# 
# ******************************************************************************
# *                                                                            *
# *                   Copyright (C) 2004-2010, Nangate Inc.                    *
# *                           All rights reserved.                             *
# *                                                                            *
# * Nangate and the Nangate logo are trademarks of Nangate Inc.                *
# *                                                                            *
# * All trademarks, logos, software marks, and trade names (collectively the   *
# * "Marks") in this program are proprietary to Nangate or other respective    *
# * owners that have granted Nangate the right and license to use such Marks.  *
# * You are not permitted to use the Marks without the prior written consent   *
# * of Nangate or such third party that may own the Marks.                     *
# *                                                                            *
# * This file has been provided pursuant to a License Agreement containing     *
# * restrictions on its use. This file contains valuable trade secrets and     *
# * proprietary information of Nangate Inc., and is protected by U.S. and      *
# * international laws and/or treaties.                                        *
# *                                                                            *
# * The copyright notice(s) in this file does not indicate actual or intended  *
# * publication of this file.                                                  *
# *                                                                            *
# *     NGLibraryCreator, v2010.08-HR32-SP3-2010-08-05 - build 1009061800      *
# *                                                                            *
# ******************************************************************************
# 
# 
# Running on brazil06.nangate.com.br for user Giancarlo Franciscatto (gfr).
# Local time is now Fri, 3 Dec 2010, 19:32:18.
# Main process id is 27821.

VERSION 5.6 ;
BUSBITCHARS "[]" ;
DIVIDERCHAR "/" ;

UNITS
  DATABASE MICRONS 2000 ;
END UNITS

MANUFACTURINGGRID 0.0050 ;

LAYER poly
  TYPE MASTERSLICE ;
END poly

LAYER active
  TYPE MASTERSLICE ;
END active

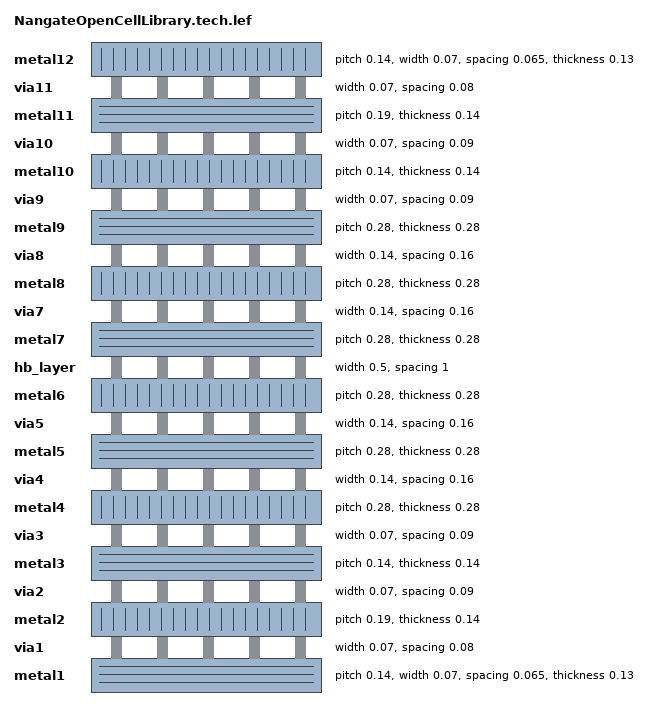
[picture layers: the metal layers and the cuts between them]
LAYER metal1
  TYPE ROUTING ;
  SPACING 0.065 ;
  WIDTH 0.07 ;
  PITCH 0.14 ;
  DIRECTION HORIZONTAL ;
  OFFSET 0.095 0.07 ;
  RESISTANCE RPERSQ 3.8 ;
  THICKNESS 0.13 ;
  HEIGHT 0.37 ;
  CAPACITANCE CPERSQDIST 7.7161e-05 ;
  EDGECAPACITANCE 2.7365e-05 ;
END metal1

LAYER via1
  TYPE CUT ;
  SPACING 0.08 ;
  WIDTH 0.07 ;
  RESISTANCE 5 ;
END via1

LAYER metal2
  TYPE ROUTING ;
  SPACINGTABLE 
    PARALLELRUNLENGTH    0.0000     0.3000     0.9000     1.8000     2.7000     4.0000     
      WIDTH 0.0000       0.0700     0.0700     0.0700     0.0700     0.0700     0.0700     
      WIDTH 0.0900       0.0700     0.0900     0.0900     0.0900     0.0900     0.0900     
      WIDTH 0.2700       0.0700     0.0900     0.2700     0.2700     0.2700     0.2700     
      WIDTH 0.5000       0.0700     0.0900     0.2700     0.5000     0.5000     0.5000     
      WIDTH 0.9000       0.0700     0.0900     0.2700     0.5000     0.9000     0.9000     
      WIDTH 1.5000       0.0700     0.0900     0.2700     0.5000     0.9000     1.5000      ;
  WIDTH 0.07 ;
  PITCH 0.19 ;
  DIRECTION VERTICAL ;
  OFFSET 0.095 0.07 ;
  RESISTANCE RPERSQ 2.5 ;
  THICKNESS 0.14 ;
  HEIGHT 0.62 ;
  CAPACITANCE CPERSQDIST 4.0896e-05 ;
  EDGECAPACITANCE 2.5157e-05 ;
END metal2

LAYER via2
  TYPE CUT ;
  SPACING 0.09 ;
  WIDTH 0.07 ;
  RESISTANCE 5 ;
END via2

LAYER metal3
  TYPE ROUTING ;
  SPACINGTABLE 
    PARALLELRUNLENGTH    0.0000     0.3000     0.9000     1.8000     2.7000     4.0000     
      WIDTH 0.0000       0.0700     0.0700     0.0700     0.0700     0.0700     0.0700     
      WIDTH 0.0900       0.0700     0.0900     0.0900     0.0900     0.0900     0.0900     
      WIDTH 0.2700       0.0700     0.0900     0.2700     0.2700     0.2700     0.2700     
      WIDTH 0.5000       0.0700     0.0900     0.2700     0.5000     0.5000     0.5000     
      WIDTH 0.9000       0.0700     0.0900     0.2700     0.5000     0.9000     0.9000     
      WIDTH 1.5000       0.0700     0.0900     0.2700     0.5000     0.9000     1.5000      ;
  WIDTH 0.07 ;
  PITCH 0.14 ;
  DIRECTION HORIZONTAL ;
  OFFSET 0.095 0.07 ;
  RESISTANCE RPERSQ 2.5 ;
  THICKNESS 0.14 ;
  HEIGHT 0.88 ;
  CAPACITANCE CPERSQDIST 2.7745e-05 ;
  EDGECAPACITANCE 2.5157e-05 ;
END metal3

LAYER via3
  TYPE CUT ;
  SPACING 0.09 ;
  WIDTH 0.07 ;
  RESISTANCE 5 ;
END via3

LAYER metal4
  TYPE ROUTING ;
  SPACINGTABLE 
    PARALLELRUNLENGTH    0.0000     0.9000     1.8000     2.7000     4.0000     
      WIDTH 0.0000       0.1400     0.1400     0.1400     0.1400     0.1400     
      WIDTH 0.2700       0.1400     0.2700     0.2700     0.2700     0.2700     
      WIDTH 0.5000       0.1400     0.2700     0.5000     0.5000     0.5000     
      WIDTH 0.9000       0.1400     0.2700     0.5000     0.9000     0.9000     
      WIDTH 1.5000       0.1400     0.2700     0.5000     0.9000     1.5000      ;
  WIDTH 0.14 ;
  PITCH 0.28 ;
  DIRECTION VERTICAL ;
  OFFSET 0.095 0.07 ;
  RESISTANCE RPERSQ 2.1 ;
  THICKNESS 0.28 ;
  HEIGHT 1.14 ;
  CAPACITANCE CPERSQDIST 2.0743e-05 ;
  EDGECAPACITANCE 3.0908e-05 ;
END metal4

LAYER via4
  TYPE CUT ;
  SPACING 0.16 ;
  WIDTH 0.14 ;
  RESISTANCE 3 ;
END via4

LAYER metal5
  TYPE ROUTING ;
  SPACINGTABLE 
    PARALLELRUNLENGTH    0.0000     0.9000     1.8000     2.7000     4.0000     
      WIDTH 0.0000       0.1400     0.1400     0.1400     0.1400     0.1400     
      WIDTH 0.2700       0.1400     0.2700     0.2700     0.2700     0.2700     
      WIDTH 0.5000       0.1400     0.2700     0.5000     0.5000     0.5000     
      WIDTH 0.9000       0.1400     0.2700     0.5000     0.9000     0.9000     
      WIDTH 1.5000       0.1400     0.2700     0.5000     0.9000     1.5000      ;
  WIDTH 0.14 ;
  PITCH 0.28 ;
  DIRECTION HORIZONTAL ;
  OFFSET 0.095 0.07 ;
  RESISTANCE RPERSQ 2.1 ;
  THICKNESS 0.28 ;
  HEIGHT 1.71 ;
  CAPACITANCE CPERSQDIST 1.3527e-05 ;
  EDGECAPACITANCE 2.3863e-06 ;
END metal5

LAYER via5
  TYPE CUT ;
  SPACING 0.16 ;
  WIDTH 0.14 ;
  RESISTANCE 3 ;
END via5

LAYER metal6
  TYPE ROUTING ;
  SPACINGTABLE 
    PARALLELRUNLENGTH    0.0000     0.9000     1.8000     2.7000     4.0000     
      WIDTH 0.0000       0.1400     0.1400     0.1400     0.1400     0.1400     
      WIDTH 0.2700       0.1400     0.2700     0.2700     0.2700     0.2700     
      WIDTH 0.5000       0.1400     0.2700     0.5000     0.5000     0.5000     
      WIDTH 0.9000       0.1400     0.2700     0.5000     0.9000     0.9000     
      WIDTH 1.5000       0.1400     0.2700     0.5000     0.9000     1.5000      ;
  WIDTH 0.14 ;
  PITCH 0.28 ;
  DIRECTION VERTICAL ;
  OFFSET 0.095 0.07 ;
  RESISTANCE RPERSQ 2.1 ;
  THICKNESS 0.28 ;
  HEIGHT 2.28 ;
  CAPACITANCE CPERSQDIST 1.0036e-05 ;
  EDGECAPACITANCE 2.3863e-05 ;
END metal6









LAYER hb_layer
  TYPE CUT ;
  SPACING 1 ;
  WIDTH 0.5 ;
  RESISTANCE 0.01 ;
END hb_layer









LAYER metal7
  TYPE ROUTING ;
  SPACINGTABLE 
    PARALLELRUNLENGTH    0.0000     0.9000     1.8000     2.7000     4.0000     
      WIDTH 0.0000       0.1400     0.1400     0.1400     0.1400     0.1400     
      WIDTH 0.2700       0.1400     0.2700     0.2700     0.2700     0.2700     
      WIDTH 0.5000       0.1400     0.2700     0.5000     0.5000     0.5000     
      WIDTH 0.9000       0.1400     0.2700     0.5000     0.9000     0.9000     
      WIDTH 1.5000       0.1400     0.2700     0.5000     0.9000     1.5000      ;
  WIDTH 0.14 ;
  PITCH 0.28 ;
  DIRECTION HORIZONTAL ;
  OFFSET 0.095 0.07 ;
  RESISTANCE RPERSQ 2.1 ;
  THICKNESS 0.28 ;
  HEIGHT 2.28 ;
  CAPACITANCE CPERSQDIST 1.0036e-05 ;
  EDGECAPACITANCE 2.3863e-05 ;
END metal7

LAYER via7
  TYPE CUT ;
  SPACING 0.16 ;
  WIDTH 0.14 ;
  RESISTANCE 3 ;
END via7

LAYER metal8
  TYPE ROUTING ;
  SPACINGTABLE 
    PARALLELRUNLENGTH    0.0000     0.9000     1.8000     2.7000     4.0000     
      WIDTH 0.0000       0.1400     0.1400     0.1400     0.1400     0.1400     
      WIDTH 0.2700       0.1400     0.2700     0.2700     0.2700     0.2700     
      WIDTH 0.5000       0.1400     0.2700     0.5000     0.5000     0.5000     
      WIDTH 0.9000       0.1400     0.2700     0.5000     0.9000     0.9000     
      WIDTH 1.5000       0.1400     0.2700     0.5000     0.9000     1.5000      ;
  WIDTH 0.14 ;
  PITCH 0.28 ;
  DIRECTION VERTICAL ;
  OFFSET 0.095 0.07 ;
  RESISTANCE RPERSQ 2.1 ;
  THICKNESS 0.28 ;
  HEIGHT 1.71 ;
  CAPACITANCE CPERSQDIST 1.3527e-05 ;
  EDGECAPACITANCE 2.3863e-06 ;
END metal8

LAYER via8
  TYPE CUT ;
  SPACING 0.16 ;
  WIDTH 0.14 ;
  RESISTANCE 3 ;
END via8

LAYER metal9
  TYPE ROUTING ;
  SPACINGTABLE 
    PARALLELRUNLENGTH    0.0000     0.9000     1.8000     2.7000     4.0000     
      WIDTH 0.0000       0.1400     0.1400     0.1400     0.1400     0.1400     
      WIDTH 0.2700       0.1400     0.2700     0.2700     0.2700     0.2700     
      WIDTH 0.5000       0.1400     0.2700     0.5000     0.5000     0.5000     
      WIDTH 0.9000       0.1400     0.2700     0.5000     0.9000     0.9000     
      WIDTH 1.5000       0.1400     0.2700     0.5000     0.9000     1.5000      ;
  WIDTH 0.14 ;
  PITCH 0.28 ;
  DIRECTION HORIZONTAL ;
  OFFSET 0.095 0.07 ;
  RESISTANCE RPERSQ 2.1 ;
  THICKNESS 0.28 ;
  HEIGHT 1.14 ;
  CAPACITANCE CPERSQDIST 2.0743e-05 ;
  EDGECAPACITANCE 3.0908e-05 ;
END metal9

LAYER via9
  TYPE CUT ;
  SPACING 0.09 ;
  WIDTH 0.07 ;
  RESISTANCE 5 ;
END via9

LAYER metal10
  TYPE ROUTING ;
  SPACINGTABLE 
    PARALLELRUNLENGTH    0.0000     0.3000     0.9000     1.8000     2.7000     4.0000     
      WIDTH 0.0000       0.0700     0.0700     0.0700     0.0700     0.0700     0.0700     
      WIDTH 0.0900       0.0700     0.0900     0.0900     0.0900     0.0900     0.0900     
      WIDTH 0.2700       0.0700     0.0900     0.2700     0.2700     0.2700     0.2700     
      WIDTH 0.5000       0.0700     0.0900     0.2700     0.5000     0.5000     0.5000     
      WIDTH 0.9000       0.0700     0.0900     0.2700     0.5000     0.9000     0.9000     
      WIDTH 1.5000       0.0700     0.0900     0.2700     0.5000     0.9000     1.5000      ;
  WIDTH 0.07 ;
  PITCH 0.14 ;
  DIRECTION VERTICAL ;
  OFFSET 0.095 0.07 ;
  RESISTANCE RPERSQ 2.5 ;
  THICKNESS 0.14 ;
  HEIGHT 0.88 ;
  CAPACITANCE CPERSQDIST 2.7745e-05 ;
  EDGECAPACITANCE 2.5157e-05 ;
END metal10

LAYER via10
  TYPE CUT ;
  SPACING 0.09 ;
  WIDTH 0.07 ;
  RESISTANCE 5 ;
END via10

LAYER metal11
  TYPE ROUTING ;
  SPACINGTABLE 
    PARALLELRUNLENGTH    0.0000     0.3000     0.9000     1.8000     2.7000     4.0000     
      WIDTH 0.0000       0.0700     0.0700     0.0700     0.0700     0.0700     0.0700     
      WIDTH 0.0900       0.0700     0.0900     0.0900     0.0900     0.0900     0.0900     
      WIDTH 0.2700       0.0700     0.0900     0.2700     0.2700     0.2700     0.2700     
      WIDTH 0.5000       0.0700     0.0900     0.2700     0.5000     0.5000     0.5000     
      WIDTH 0.9000       0.0700     0.0900     0.2700     0.5000     0.9000     0.9000     
      WIDTH 1.5000       0.0700     0.0900     0.2700     0.5000     0.9000     1.5000      ;
  WIDTH 0.07 ;
  PITCH 0.19 ;
  DIRECTION HORIZONTAL ;
  OFFSET 0.095 0.07 ;
  RESISTANCE RPERSQ 2.5 ;
  THICKNESS 0.14 ;
  HEIGHT 0.62 ;
  CAPACITANCE CPERSQDIST 4.0896e-05 ;
  EDGECAPACITANCE 2.5157e-05 ;
END metal11

LAYER via11
  TYPE CUT ;
  SPACING 0.08 ;
  WIDTH 0.07 ;
  RESISTANCE 5 ;
END via11

LAYER metal12
  TYPE ROUTING ;
  SPACING 0.065 ;
  WIDTH 0.07 ;
  PITCH 0.14 ;
  DIRECTION VERTICAL ;
  OFFSET 0.095 0.07 ;
  RESISTANCE RPERSQ 3.8 ;
  THICKNESS 0.13 ;
  HEIGHT 0.37 ;
  CAPACITANCE CPERSQDIST 7.7161e-05 ;
  EDGECAPACITANCE 2.7365e-05 ;
END metal12

LAYER OVERLAP
  TYPE OVERLAP ;
END OVERLAP

VIA via1_4 DEFAULT
  LAYER via1 ;
    RECT -0.035 -0.035 0.035 0.035 ;
  LAYER metal1 ;
    RECT -0.035 -0.07 0.035 0.07 ;
  LAYER metal2 ;
    RECT -0.035 -0.07 0.035 0.07 ;
END via1_4

VIA via1_0 DEFAULT
  LAYER via1 ;
    RECT -0.035 -0.035 0.035 0.035 ;
  LAYER metal1 ;
    RECT -0.07 -0.07 0.07 0.07 ;
  LAYER metal2 ;
    RECT -0.07 -0.07 0.07 0.07 ;
END via1_0

VIA via1_1 DEFAULT
  LAYER via1 ;
    RECT -0.035 -0.035 0.035 0.035 ;
  LAYER metal1 ;
    RECT -0.07 -0.07 0.07 0.07 ;
  LAYER metal2 ;
    RECT -0.035 -0.07 0.035 0.07 ;
END via1_1

VIA via1_2 DEFAULT
  LAYER via1 ;
    RECT -0.035 -0.035 0.035 0.035 ;
  LAYER metal1 ;
    RECT -0.07 -0.07 0.07 0.07 ;
  LAYER metal2 ;
    RECT -0.07 -0.035 0.07 0.035 ;
END via1_2

VIA via1_3 DEFAULT
  LAYER via1 ;
    RECT -0.035 -0.035 0.035 0.035 ;
  LAYER metal1 ;
    RECT -0.035 -0.07 0.035 0.07 ;
  LAYER metal2 ;
    RECT -0.07 -0.07 0.07 0.07 ;
END via1_3

VIA via1_5 DEFAULT
  LAYER via1 ;
    RECT -0.035 -0.035 0.035 0.035 ;
  LAYER metal1 ;
    RECT -0.035 -0.07 0.035 0.07 ;
  LAYER metal2 ;
    RECT -0.07 -0.035 0.07 0.035 ;
END via1_5

VIA via1_6 DEFAULT
  LAYER via1 ;
    RECT -0.035 -0.035 0.035 0.035 ;
  LAYER metal1 ;
    RECT -0.07 -0.035 0.07 0.035 ;
  LAYER metal2 ;
    RECT -0.07 -0.07 0.07 0.07 ;
END via1_6

VIA via1_7 DEFAULT
  LAYER via1 ;
    RECT -0.035 -0.035 0.035 0.035 ;
  LAYER metal1 ;
    RECT -0.07 -0.035 0.07 0.035 ;
  LAYER metal2 ;
    RECT -0.035 -0.07 0.035 0.07 ;
END via1_7

VIA via1_8 DEFAULT
  LAYER via1 ;
    RECT -0.035 -0.035 0.035 0.035 ;
  LAYER metal1 ;
    RECT -0.07 -0.035 0.07 0.035 ;
  LAYER metal2 ;
    RECT -0.07 -0.035 0.07 0.035 ;
END via1_8

VIA via2_8 DEFAULT
  LAYER via2 ;
    RECT -0.035 -0.035 0.035 0.035 ;
  LAYER metal2 ;
    RECT -0.07 -0.035 0.07 0.035 ;
  LAYER metal3 ;
    RECT -0.07 -0.035 0.07 0.035 ;
END via2_8

VIA via2_4 DEFAULT
  LAYER via2 ;
    RECT -0.035 -0.035 0.035 0.035 ;
  LAYER metal2 ;
    RECT -0.035 -0.07 0.035 0.07 ;
  LAYER metal3 ;
    RECT -0.035 -0.07 0.035 0.07 ;
END via2_4

VIA via2_5 DEFAULT
  LAYER via2 ;
    RECT -0.035 -0.035 0.035 0.035 ;
  LAYER metal2 ;
    RECT -0.035 -0.07 0.035 0.07 ;
  LAYER metal3 ;
    RECT -0.07 -0.035 0.07 0.035 ;
END via2_5

VIA via2_7 DEFAULT
  LAYER via2 ;
    RECT -0.035 -0.035 0.035 0.035 ;
  LAYER metal2 ;
    RECT -0.07 -0.035 0.07 0.035 ;
  LAYER metal3 ;
    RECT -0.035 -0.07 0.035 0.07 ;
END via2_7

VIA via2_6 DEFAULT
  LAYER via2 ;
    RECT -0.035 -0.035 0.035 0.035 ;
  LAYER metal2 ;
    RECT -0.07 -0.035 0.07 0.035 ;
  LAYER metal3 ;
    RECT -0.07 -0.07 0.07 0.07 ;
END via2_6

VIA via2_0 DEFAULT
  LAYER via2 ;
    RECT -0.035 -0.035 0.035 0.035 ;
  LAYER metal2 ;
    RECT -0.07 -0.07 0.07 0.07 ;
  LAYER metal3 ;
    RECT -0.07 -0.07 0.07 0.07 ;
END via2_0

VIA via2_1 DEFAULT
  LAYER via2 ;
    RECT -0.035 -0.035 0.035 0.035 ;
  LAYER metal2 ;
    RECT -0.07 -0.07 0.07 0.07 ;
  LAYER metal3 ;
    RECT -0.035 -0.07 0.035 0.07 ;
END via2_1

VIA via2_2 DEFAULT
  LAYER via2 ;
    RECT -0.035 -0.035 0.035 0.035 ;
  LAYER metal2 ;
    RECT -0.07 -0.07 0.07 0.07 ;
  LAYER metal3 ;
    RECT -0.07 -0.035 0.07 0.035 ;
END via2_2

VIA via2_3 DEFAULT
  LAYER via2 ;
    RECT -0.035 -0.035 0.035 0.035 ;
  LAYER metal2 ;
    RECT -0.035 -0.07 0.035 0.07 ;
  LAYER metal3 ;
    RECT -0.07 -0.07 0.07 0.07 ;
END via2_3

VIA via3_2 DEFAULT
  LAYER via3 ;
    RECT -0.035 -0.035 0.035 0.035 ;
  LAYER metal3 ;
    RECT -0.07 -0.035 0.07 0.035 ;
  LAYER metal4 ;
    RECT -0.07 -0.07 0.07 0.07 ;
END via3_2

VIA via3_0 DEFAULT
  LAYER via3 ;
    RECT -0.035 -0.035 0.035 0.035 ;
  LAYER metal3 ;
    RECT -0.07 -0.07 0.07 0.07 ;
  LAYER metal4 ;
    RECT -0.07 -0.07 0.07 0.07 ;
END via3_0

VIA via3_1 DEFAULT
  LAYER via3 ;
    RECT -0.035 -0.035 0.035 0.035 ;
  LAYER metal3 ;
    RECT -0.035 -0.07 0.035 0.07 ;
  LAYER metal4 ;
    RECT -0.07 -0.07 0.07 0.07 ;
END via3_1

VIA via4_0 DEFAULT
  LAYER via4 ;
    RECT -0.07 -0.07 0.07 0.07 ;
  LAYER metal4 ;
    RECT -0.07 -0.07 0.07 0.07 ;
  LAYER metal5 ;
    RECT -0.07 -0.07 0.07 0.07 ;
END via4_0

VIA via5_0 DEFAULT
  LAYER via5 ;
    RECT -0.07 -0.07 0.07 0.07 ;
  LAYER metal5 ;
    RECT -0.07 -0.07 0.07 0.07 ;
  LAYER metal6 ;
    RECT -0.07 -0.07 0.07 0.07 ;
END via5_0





VIA hb_layer_0 DEFAULT
  LAYER hb_layer ;
    RECT -0.25 -0.25 0.25 0.25 ;
  LAYER metal6 ;
    RECT -0.25 -0.25 0.25 0.25 ;
  LAYER metal7 ;
    RECT -0.25 -0.25 0.25 0.25 ;
END hb_layer_0





VIA via7_0 DEFAULT
  LAYER via7 ;
    RECT -0.07 -0.07 0.07 0.07 ;
  LAYER metal7 ;
    RECT -0.07 -0.07 0.07 0.07 ;
  LAYER metal8 ;
    RECT -0.07 -0.07 0.07 0.07 ;
END via7_0

VIA via8_0 DEFAULT
  LAYER via8 ;
    RECT -0.07 -0.07 0.07 0.07 ;
  LAYER metal8 ;
    RECT -0.07 -0.07 0.07 0.07 ;
  LAYER metal9 ;
    RECT -0.07 -0.07 0.07 0.07 ;
END via8_0

VIA via9_2 DEFAULT
  LAYER via9 ;
    RECT -0.035 -0.035 0.035 0.035 ;
  LAYER metal9 ;
    RECT -0.07 -0.035 0.07 0.035 ;
  LAYER metal10 ;
    RECT -0.07 -0.07 0.07 0.07 ;
END via9_2

VIA via9_0 DEFAULT
  LAYER via9 ;
    RECT -0.035 -0.035 0.035 0.035 ;
  LAYER metal9 ;
    RECT -0.07 -0.07 0.07 0.07 ;
  LAYER metal10 ;
    RECT -0.07 -0.07 0.07 0.07 ;
END via9_0

VIA via9_1 DEFAULT
  LAYER via9 ;
    RECT -0.035 -0.035 0.035 0.035 ;
  LAYER metal9 ;
    RECT -0.035 -0.07 0.035 0.07 ;
  LAYER metal10 ;
    RECT -0.07 -0.07 0.07 0.07 ;
END via9_1

VIA via10_8 DEFAULT
  LAYER via10 ;
    RECT -0.035 -0.035 0.035 0.035 ;
  LAYER metal10 ;
    RECT -0.07 -0.035 0.07 0.035 ;
  LAYER metal11 ;
    RECT -0.07 -0.035 0.07 0.035 ;
END via10_8

VIA via10_4 DEFAULT
  LAYER via10 ;
    RECT -0.035 -0.035 0.035 0.035 ;
  LAYER metal10 ;
    RECT -0.035 -0.07 0.035 0.07 ;
  LAYER metal11 ;
    RECT -0.035 -0.07 0.035 0.07 ;
END via10_4

VIA via10_5 DEFAULT
  LAYER via10 ;
    RECT -0.035 -0.035 0.035 0.035 ;
  LAYER metal10 ;
    RECT -0.035 -0.07 0.035 0.07 ;
  LAYER metal11 ;
    RECT -0.07 -0.035 0.07 0.035 ;
END via10_5

VIA via10_7 DEFAULT
  LAYER via10 ;
    RECT -0.035 -0.035 0.035 0.035 ;
  LAYER metal10 ;
    RECT -0.07 -0.035 0.07 0.035 ;
  LAYER metal11 ;
    RECT -0.035 -0.07 0.035 0.07 ;
END via10_7

VIA via10_6 DEFAULT
  LAYER via10 ;
    RECT -0.035 -0.035 0.035 0.035 ;
  LAYER metal10 ;
    RECT -0.07 -0.035 0.07 0.035 ;
  LAYER metal11 ;
    RECT -0.07 -0.07 0.07 0.07 ;
END via10_6

VIA via10_0 DEFAULT
  LAYER via10 ;
    RECT -0.035 -0.035 0.035 0.035 ;
  LAYER metal10 ;
    RECT -0.07 -0.07 0.07 0.07 ;
  LAYER metal11 ;
    RECT -0.07 -0.07 0.07 0.07 ;
END via10_0

VIA via10_1 DEFAULT
  LAYER via10 ;
    RECT -0.035 -0.035 0.035 0.035 ;
  LAYER metal10 ;
    RECT -0.07 -0.07 0.07 0.07 ;
  LAYER metal11 ;
    RECT -0.035 -0.07 0.035 0.07 ;
END via10_1

VIA via10_2 DEFAULT
  LAYER via10 ;
    RECT -0.035 -0.035 0.035 0.035 ;
  LAYER metal10 ;
    RECT -0.07 -0.07 0.07 0.07 ;
  LAYER metal11 ;
    RECT -0.07 -0.035 0.07 0.035 ;
END via10_2

VIA via10_3 DEFAULT
  LAYER via10 ;
    RECT -0.035 -0.035 0.035 0.035 ;
  LAYER metal10 ;
    RECT -0.035 -0.07 0.035 0.07 ;
  LAYER metal11 ;
    RECT -0.07 -0.07 0.07 0.07 ;
END via10_3

VIA via11_4 DEFAULT
  LAYER via11 ;
    RECT -0.035 -0.035 0.035 0.035 ;
  LAYER metal11 ;
    RECT -0.035 -0.07 0.035 0.07 ;
  LAYER metal12 ;
    RECT -0.035 -0.07 0.035 0.07 ;
END via11_4

VIA via11_0 DEFAULT
  LAYER via11 ;
    RECT -0.035 -0.035 0.035 0.035 ;
  LAYER metal11 ;
    RECT -0.07 -0.07 0.07 0.07 ;
  LAYER metal12 ;
    RECT -0.07 -0.07 0.07 0.07 ;
END via11_0

VIA via11_1 DEFAULT
  LAYER via11 ;
    RECT -0.035 -0.035 0.035 0.035 ;
  LAYER metal11 ;
    RECT -0.07 -0.07 0.07 0.07 ;
  LAYER metal12 ;
    RECT -0.035 -0.07 0.035 0.07 ;
END via11_1

VIA via11_2 DEFAULT
  LAYER via11 ;
    RECT -0.035 -0.035 0.035 0.035 ;
  LAYER metal11 ;
    RECT -0.07 -0.07 0.07 0.07 ;
  LAYER metal12 ;
    RECT -0.07 -0.035 0.07 0.035 ;
END via11_2

VIA via11_3 DEFAULT
  LAYER via11 ;
    RECT -0.035 -0.035 0.035 0.035 ;
  LAYER metal11 ;
    RECT -0.035 -0.07 0.035 0.07 ;
  LAYER metal12 ;
    RECT -0.07 -0.07 0.07 0.07 ;
END via11_3

VIA via11_5 DEFAULT
  LAYER via11 ;
    RECT -0.035 -0.035 0.035 0.035 ;
  LAYER metal11 ;
    RECT -0.035 -0.07 0.035 0.07 ;
  LAYER metal12 ;
    RECT -0.07 -0.035 0.07 0.035 ;
END via11_5

VIA via11_6 DEFAULT
  LAYER via11 ;
    RECT -0.035 -0.035 0.035 0.035 ;
  LAYER metal11 ;
    RECT -0.07 -0.035 0.07 0.035 ;
  LAYER metal12 ;
    RECT -0.07 -0.07 0.07 0.07 ;
END via11_6

VIA via11_7 DEFAULT
  LAYER via11 ;
    RECT -0.035 -0.035 0.035 0.035 ;
  LAYER metal11 ;
    RECT -0.07 -0.035 0.07 0.035 ;
  LAYER metal12 ;
    RECT -0.035 -0.07 0.035 0.07 ;
END via11_7

VIA via11_8 DEFAULT
  LAYER via11 ;
    RECT -0.035 -0.035 0.035 0.035 ;
  LAYER metal11 ;
    RECT -0.07 -0.035 0.07 0.035 ;
  LAYER metal12 ;
    RECT -0.07 -0.035 0.07 0.035 ;
END via11_8

VIARULE Via1Array-0 GENERATE
  LAYER metal1 ;
    ENCLOSURE 0.035 0.035 ;
  LAYER metal2 ;
    ENCLOSURE 0.035 0.035 ;
  LAYER via1 ;
    RECT -0.035 -0.035 0.035 0.035 ;
    SPACING 0.15 BY 0.15 ;
END Via1Array-0

VIARULE Via1Array-1 GENERATE
  LAYER metal1 ;
    ENCLOSURE 0 0.035 ;
  LAYER metal2 ;
    ENCLOSURE 0 0.035 ;
  LAYER via1 ;
    RECT -0.035 -0.035 0.035 0.035 ;
    SPACING 0.15 BY 0.15 ;
END Via1Array-1

VIARULE Via1Array-2 GENERATE
  LAYER metal1 ;
    ENCLOSURE 0.035 0 ;
  LAYER metal2 ;
    ENCLOSURE 0.035 0 ;
  LAYER via1 ;
    RECT -0.035 -0.035 0.035 0.035 ;
    SPACING 0.15 BY 0.15 ;
END Via1Array-2

VIARULE Via1Array-3 GENERATE
  LAYER metal1 ;
    ENCLOSURE 0 0.035 ;
  LAYER metal2 ;
    ENCLOSURE 0.035 0 ;
  LAYER via1 ;
    RECT -0.035 -0.035 0.035 0.035 ;
    SPACING 0.15 BY 0.15 ;
END Via1Array-3

VIARULE Via1Array-4 GENERATE
  LAYER metal1 ;
    ENCLOSURE 0.035 0 ;
  LAYER metal2 ;
    ENCLOSURE 0 0.035 ;
  LAYER via1 ;
    RECT -0.035 -0.035 0.035 0.035 ;
    SPACING 0.15 BY 0.15 ;
END Via1Array-4

VIARULE Via2Array-0 GENERATE
  LAYER metal2 ;
    ENCLOSURE 0.035 0.035 ;
  LAYER metal3 ;
    ENCLOSURE 0.035 0.035 ;
  LAYER via2 ;
    RECT -0.035 -0.035 0.035 0.035 ;
    SPACING 0.16 BY 0.16 ;
END Via2Array-0

VIARULE Via2Array-1 GENERATE
  LAYER metal2 ;
    ENCLOSURE 0 0.035 ;
  LAYER metal3 ;
    ENCLOSURE 0 0.035 ;
  LAYER via2 ;
    RECT -0.035 -0.035 0.035 0.035 ;
    SPACING 0.16 BY 0.16 ;
END Via2Array-1

VIARULE Via2Array-2 GENERATE
  LAYER metal2 ;
    ENCLOSURE 0.035 0 ;
  LAYER metal3 ;
    ENCLOSURE 0.035 0 ;
  LAYER via2 ;
    RECT -0.035 -0.035 0.035 0.035 ;
    SPACING 0.16 BY 0.16 ;
END Via2Array-2

VIARULE Via2Array-3 GENERATE
  LAYER metal2 ;
    ENCLOSURE 0 0.035 ;
  LAYER metal3 ;
    ENCLOSURE 0.035 0 ;
  LAYER via2 ;
    RECT -0.035 -0.035 0.035 0.035 ;
    SPACING 0.16 BY 0.16 ;
END Via2Array-3

VIARULE Via2Array-4 GENERATE
  LAYER metal2 ;
    ENCLOSURE 0.035 0 ;
  LAYER metal3 ;
    ENCLOSURE 0 0.035 ;
  LAYER via2 ;
    RECT -0.035 -0.035 0.035 0.035 ;
    SPACING 0.16 BY 0.16 ;
END Via2Array-4

VIARULE Via3Array-0 GENERATE
  LAYER metal3 ;
    ENCLOSURE 0.035 0.035 ;
  LAYER metal4 ;
    ENCLOSURE 0.035 0.035 ;
  LAYER via3 ;
    RECT -0.035 -0.035 0.035 0.035 ;
    SPACING 0.16 BY 0.16 ;
END Via3Array-0

VIARULE Via3Array-1 GENERATE
  LAYER metal3 ;
    ENCLOSURE 0 0.035 ;
  LAYER metal4 ;
    ENCLOSURE 0.035 0.035 ;
  LAYER via3 ;
    RECT -0.035 -0.035 0.035 0.035 ;
    SPACING 0.16 BY 0.16 ;
END Via3Array-1

VIARULE Via3Array-2 GENERATE
  LAYER metal3 ;
    ENCLOSURE 0.035 0 ;
  LAYER metal4 ;
    ENCLOSURE 0.035 0.035 ;
  LAYER via3 ;
    RECT -0.035 -0.035 0.035 0.035 ;
    SPACING 0.16 BY 0.16 ;
END Via3Array-2

VIARULE Via4Array-0 GENERATE
  LAYER metal4 ;
    ENCLOSURE 0 0 ;
  LAYER metal5 ;
    ENCLOSURE 0 0 ;
  LAYER via4 ;
    RECT -0.07 -0.07 0.07 0.07 ;
    SPACING 0.3 BY 0.3 ;
END Via4Array-0

VIARULE Via5Array-0 GENERATE
  LAYER metal5 ;
    ENCLOSURE 0 0 ;
  LAYER metal6 ;
    ENCLOSURE 0 0 ;
  LAYER via5 ;
    RECT -0.07 -0.07 0.07 0.07 ;
    SPACING 0.3 BY 0.3 ;
END Via5Array-0





VIARULE hb_layerArray-0 GENERATE
  LAYER metal7 ;
    ENCLOSURE 0 0 ;
  LAYER metal6 ;
    ENCLOSURE 0 0 ;
  LAYER hb_layer ;
    RECT -0.25 -0.25 0.25 0.25 ;
    SPACING 1 BY 1 ;
END hb_layerArray-0





VIARULE Via7Array-0 GENERATE
  LAYER metal7 ;
    ENCLOSURE 0 0 ;
  LAYER metal8 ;
    ENCLOSURE 0 0 ;
  LAYER via7 ;
    RECT -0.07 -0.07 0.07 0.07 ;
    SPACING 0.3 BY 0.3 ;
END Via7Array-0

VIARULE Via8Array-0 GENERATE
  LAYER metal8 ;
    ENCLOSURE 0 0 ;
  LAYER metal9 ;
    ENCLOSURE 0 0 ;
  LAYER via8 ;
    RECT -0.07 -0.07 0.07 0.07 ;
    SPACING 0.3 BY 0.3 ;
END Via8Array-0

VIARULE Via9Array-0 GENERATE
  LAYER metal9 ;
    ENCLOSURE 0.035 0.035 ;
  LAYER metal10 ;
    ENCLOSURE 0.035 0.035 ;
  LAYER via9 ;
    RECT -0.035 -0.035 0.035 0.035 ;
    SPACING 0.16 BY 0.16 ;
END Via9Array-0

VIARULE Via9Array-1 GENERATE
  LAYER metal9 ;
    ENCLOSURE 0 0.035 ;
  LAYER metal10 ;
    ENCLOSURE 0.035 0.035 ;
  LAYER via9 ;
    RECT -0.035 -0.035 0.035 0.035 ;
    SPACING 0.16 BY 0.16 ;
END Via9Array-1

VIARULE Via9Array-2 GENERATE
  LAYER metal9 ;
    ENCLOSURE 0.035 0 ;
  LAYER metal10 ;
    ENCLOSURE 0.035 0.035 ;
  LAYER via9 ;
    RECT -0.035 -0.035 0.035 0.035 ;
    SPACING 0.16 BY 0.16 ;
END Via9Array-2

VIARULE Via10Array-0 GENERATE
  LAYER metal10 ;
    ENCLOSURE 0.035 0.035 ;
  LAYER metal11 ;
    ENCLOSURE 0.035 0.035 ;
  LAYER via10 ;
    RECT -0.035 -0.035 0.035 0.035 ;
    SPACING 0.16 BY 0.16 ;
END Via10Array-0

VIARULE Via10Array-1 GENERATE
  LAYER metal10 ;
    ENCLOSURE 0 0.035 ;
  LAYER metal11 ;
    ENCLOSURE 0 0.035 ;
  LAYER via10 ;
    RECT -0.035 -0.035 0.035 0.035 ;
    SPACING 0.16 BY 0.16 ;
END Via10Array-1

VIARULE Via10Array-2 GENERATE
  LAYER metal10 ;
    ENCLOSURE 0.035 0 ;
  LAYER metal11 ;
    ENCLOSURE 0.035 0 ;
  LAYER via10 ;
    RECT -0.035 -0.035 0.035 0.035 ;
    SPACING 0.16 BY 0.16 ;
END Via10Array-2

VIARULE Via10Array-3 GENERATE
  LAYER metal10 ;
    ENCLOSURE 0 0.035 ;
  LAYER metal11 ;
    ENCLOSURE 0.035 0 ;
  LAYER via10 ;
    RECT -0.035 -0.035 0.035 0.035 ;
    SPACING 0.16 BY 0.16 ;
END Via10Array-3

VIARULE Via10Array-4 GENERATE
  LAYER metal10 ;
    ENCLOSURE 0.035 0 ;
  LAYER metal11 ;
    ENCLOSURE 0 0.035 ;
  LAYER via10 ;
    RECT -0.035 -0.035 0.035 0.035 ;
    SPACING 0.16 BY 0.16 ;
END Via10Array-4

VIARULE Via11Array-0 GENERATE
  LAYER metal11 ;
    ENCLOSURE 0.035 0.035 ;
  LAYER metal12 ;
    ENCLOSURE 0.035 0.035 ;
  LAYER via11 ;
    RECT -0.035 -0.035 0.035 0.035 ;
    SPACING 0.15 BY 0.15 ;
END Via11Array-0

VIARULE Via11Array-1 GENERATE
  LAYER metal11 ;
    ENCLOSURE 0 0.035 ;
  LAYER metal12 ;
    ENCLOSURE 0 0.035 ;
  LAYER via11 ;
    RECT -0.035 -0.035 0.035 0.035 ;
    SPACING 0.15 BY 0.15 ;
END Via11Array-1

VIARULE Via11Array-2 GENERATE
  LAYER metal11 ;
    ENCLOSURE 0.035 0 ;
  LAYER metal12 ;
    ENCLOSURE 0.035 0 ;
  LAYER via11 ;
    RECT -0.035 -0.035 0.035 0.035 ;
    SPACING 0.15 BY 0.15 ;
END Via11Array-2

VIARULE Via11Array-3 GENERATE
  LAYER metal11 ;
    ENCLOSURE 0 0.035 ;
  LAYER metal12 ;
    ENCLOSURE 0.035 0 ;
  LAYER via11 ;
    RECT -0.035 -0.035 0.035 0.035 ;
    SPACING 0.15 BY 0.15 ;
END Via11Array-3

VIARULE Via11Array-4 GENERATE
  LAYER metal11 ;
    ENCLOSURE 0.035 0 ;
  LAYER metal12 ;
    ENCLOSURE 0 0.035 ;
  LAYER via11 ;
    RECT -0.035 -0.035 0.035 0.035 ;
    SPACING 0.15 BY 0.15 ;
END Via11Array-4

SPACING
  SAMENET metal1 metal1 0.065 ;
  SAMENET metal2 metal2 0.07 ;
  SAMENET metal3 metal3 0.07 ;
  SAMENET metal4 metal4 0.14 ;
  SAMENET metal5 metal5 0.14 ;
  SAMENET metal6 metal6 0.14 ;
  SAMENET metal7 metal7 0.14 ;
  SAMENET metal8 metal8 0.14 ;
  SAMENET metal9 metal9 0.14 ;
  SAMENET metal10 metal10 0.07 ;
  SAMENET metal11 metal11 0.07 ;
  SAMENET metal12 metal12 0.065 ;
  SAMENET via1 via1 0.08 ;
  SAMENET via2 via2 0.09 ;
  SAMENET via3 via3 0.09 ;
  SAMENET via4 via4 0.16 ;
  SAMENET via5 via5 0.16 ;
  SAMENET via7 via7 0.16 ;
  SAMENET via8 via8 0.16 ;
  SAMENET via9 via9 0.09 ;
  SAMENET via10 via10 0.09 ;
  SAMENET via11 via11 0.08 ;
  SAMENET hb_layer hb_layer 1.0 ;
  SAMENET via1 via2 0.0 STACK ;
  SAMENET via2 via3 0.0 STACK ;
  SAMENET via3 via4 0.0 STACK ;
  SAMENET via4 via5 0.0 STACK ;
  SAMENET via5 hb_layer 0.0 STACK ;
  SAMENET hb_layer via7 0.0 STACK ;
  SAMENET via7 via8 0.0 STACK ;
  SAMENET via8 via9 0.0 STACK ;
  SAMENET via9 via10 0.0 STACK ;
  SAMENET via10 via11 0.0 STACK ;
END SPACING
SITE FreePDK45_38x28_10R_NP_162NW_34O
  SYMMETRY y ;
  CLASS core ;
  SIZE 0.19 BY 1.4 ;
END FreePDK45_38x28_10R_NP_162NW_34O

END LIBRARY
#
# End of file
#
